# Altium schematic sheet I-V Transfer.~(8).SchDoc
size A4

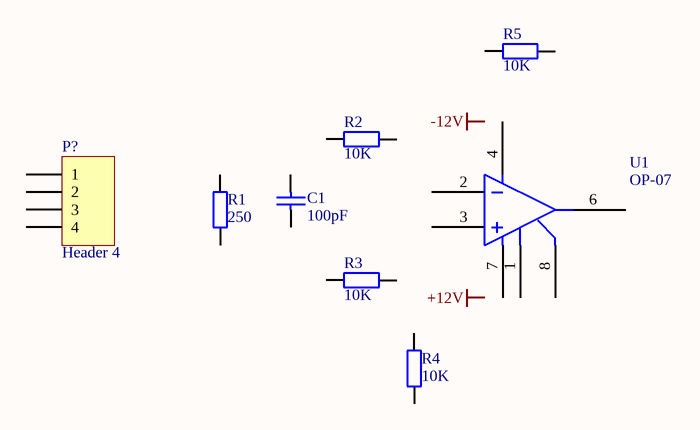
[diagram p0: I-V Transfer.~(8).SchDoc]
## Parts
C1  value 100pF  [RAD-0.3]  (hidden comment: Cap)
P?  Header 4  [HDR1X4]
R1  value 250  [AXIAL-0.4]  (hidden comment: Res2)
R2  value 10K  [AXIAL-0.4]  (hidden comment: Res2)
R3  value 10K  [AXIAL-0.4]  (hidden comment: Res2)
R4  value 10K  [AXIAL-0.4]  (hidden comment: Res2)
R5  value 10K  [AXIAL-0.4]  (hidden comment: Res2)
U1  OP-07  [DIP-8]

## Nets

Not connected (* = marked no-connect by the designer): C1 1 2; P? 1 2 3 4; R1 1 2; R2 1 2; R3 1 2; R4 1 2; R5 1 2; U1 1 2 3 4 6 7 8

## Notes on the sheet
- Labels drawn without touching a wire or pin: +12V, -12V

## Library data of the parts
C1 = Cap: Capacitor
P? = Header 4: Header, 4-Pin
R1-R5 = Res2: Resistor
